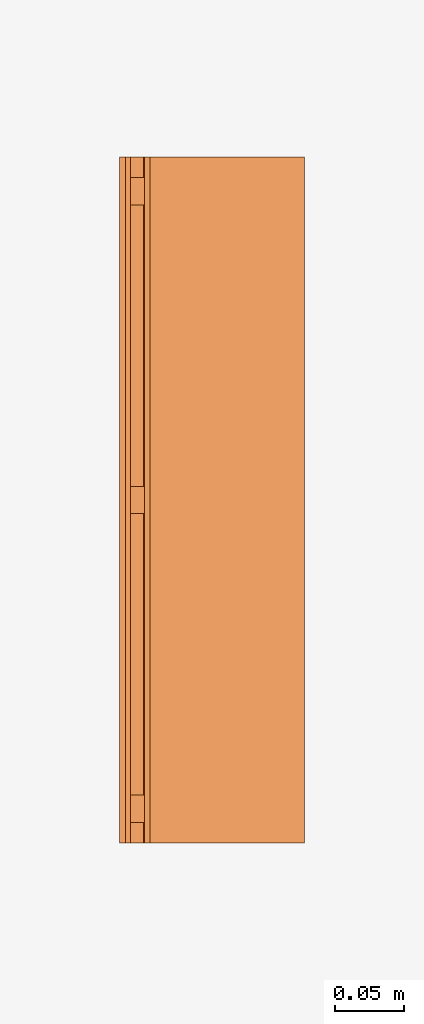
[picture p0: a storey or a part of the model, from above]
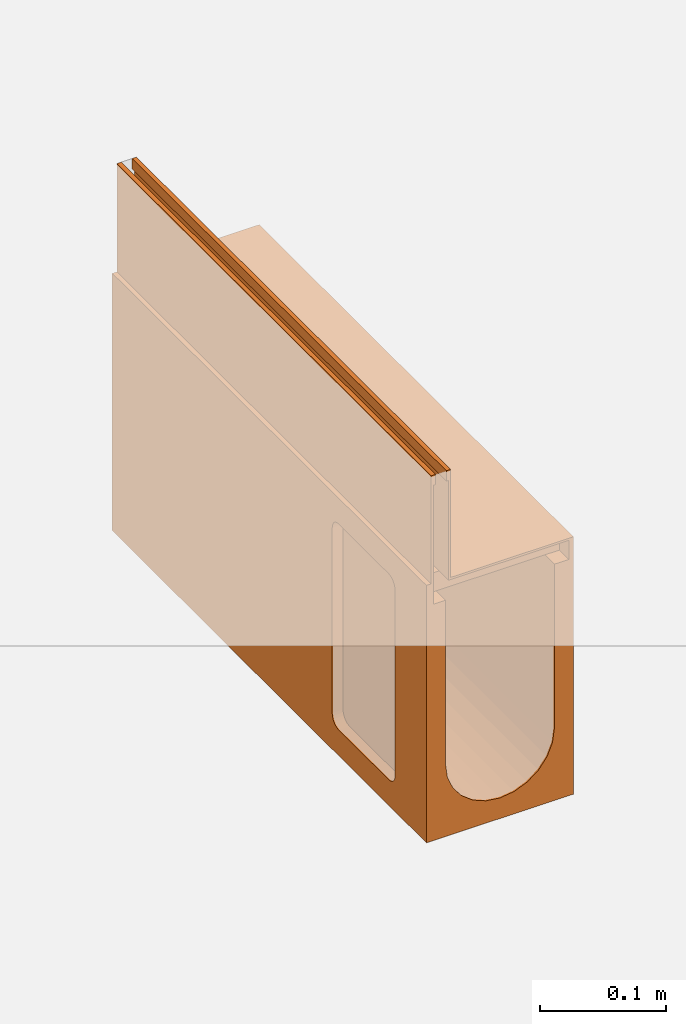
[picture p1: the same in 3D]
Properties of the parts of a building model (IFC2X3)

# File
Description: ViewDefinition [CoordinationView]
File name: 24201.ifc
Time: 2013-10-30T12:03:49
Written by: Autodesk Revit 2013
Made in: 20120221_2030(x64)

# IfcProject, Project Number
LongName: Project Name; Phase: Project Status

# IfcSite, Default
RefLatitude: 42, 21, 30, 344238; RefLongitude: -71, -3, -35, -194702; RefElevation: 0 mm

# IfcBuilding
Pset_BuildingCommon - NumberOfStoreys: 1
Other - Project Number: Project Number; Project Status: Project Status; Client Name: Owner; Project Issue Date: Issue Date; Project Address: ## Street City, State Zip; Project Name: Project Name

# IfcBuildingStorey, Level 1
LongName: Level 1; Elevation: 0 mm
Constraints - Elevation Base: 0; Elevation: 0 mm
Graphics - Color: 0; Symbol: M_Level Head - Circle: M_Level Head - Circle; Line Weight: 1; Symbol at End 2 Default: yes; Line Pattern: Center; Symbol at End 1 Default: no
Identity Data - Structural: no; Building Story: yes; Name: Level 1
Dimensions - Computation Height: 0 mm

# IfcBuildingElementProxy: 24201 - No 20.1J Constant Depth Channel - 500mm LG - Invert Depth 230mm, Civil-Drainage-Channel-ACO-MultiDrain-M100DS-Brickslot-Channel-System:24201 - No 20.1J Constant Depth Channel - 500mm LG - Invert Depth 230mm:24201 - No 20.1J Constant Depth Channel - 500mm LG - Invert Depth 230mm:196059
In: Level 1
Material: Stainless Steel (F), Vienite® Synthetic Resin Concrete
Dimensions - Volume: 5654234 mm3; FloorCut_Length: -500 mm; EndCap Position: 500 mm; Custom_Void_length: 0 mm; Brickslot Void Length: 500 mm; Brickslot Void Depth: 0 mm; Brickslot Access Unit Void Depth: -6500 mm; Brickslot Access Unit Void Bottom Depth: -6605 mm; Length: 1000 mm; FloorCut_Depth: 250 mm; InvDepth: 180 mm; FloorCut_Width: 135 mm; GratingLength: -1000 mm; Brickslot Access Unit Floor Cut Length: 500 mm; Floor Cut Gap: 105 mm; ShallowInvDepth: 55 mm; EndCap_Height: 250 mm; Length Drain: -500 mm; ShallowOverallDepth: 75 mm; Depth: 250 mm
Construction - 23404_Universal Endcap (Male End): no; 23404_Universal Endcap (Female End): no; 23477_Load Class C250 & D400_Brickslot_Access Unit_Stainless Steel_500mm Long: no; 23475_Load Class C250 & D400_Brickslot Grating_Stainless Steel_1000mm Long: no; 23476_Load Class C250 & D400_Brickslot Grating_Stainless Steel_500mm Long: yes; Constant Depth Junction Channel: yes; Shallow Depth Channel: no; Constant Depth Channel: no; 23410_Sump Unit: no; Shallow Depth Channel with seal: no
Constraints - Moves With Nearby Elements: no; Level: Level: Level 1
Phasing - Phase Created: New Construction
Pset_BuildingElementProxyCommon - Reference: 24201 - No 20.1J Constant Depth Channel - 500mm LG - Invert Depth 230mm
Identity Data - Maintenance guidelines: http://www.aco.co.uk/download.php?id=173; Cost: 0; URL: www.aco.co.uk; Watermark 2: This file is water marked and users are prohibited to reproduce, adapt, distribute this information; Type Comments: ACO MultiDrain M100DS 20.1J Constant Depth Junction Channel 500mm Long; Watermarked With: BIM Manager Premium Suite; Telephone: +44 (0)1462 816666; Watermark 1: This file is the property of ACO Technologies PLC; Address: ACO Business Park, Hitchin Road, Shefford, Bedfordshire, United Kingdom SG17 5TE; e-mail Sales: customersupport@aco.co.uk; OmniClass Title: Rainwater Removal; Model Description: Channel drainage system; e-mail Technical: technical@aco.co.uk; Product Page URL: http://www.aco.co.uk/product_detail.php?id=58; Assembly Code: D2040; Manufacturer: ACO Technologies plc - ACO Water Management Division; Price: POA - contact ACO; Installation guidelines: http://www.aco.co.uk/download.php?id=173; Model: ACO MultiDrain MDS Brickslot- M100DS; Product Code: 24201; Product brochure: http://www.aco.co.uk/download.php?id=173; OmniClass Number: 23.70.50.24; Fax: +44 (0)1462 815895; Watermarked By: www.aco.co.uk; Assembly Description: Rain Water Drainage
Green Building Properties - Channel Recycled Material Content: 20% minimum; Channel Recyclable: Fully recyclable; Edge Rail Recyclable: Fully recyclable; Edge Rail Recycled Material Content: Between 40% - 90%
Data - Load Class: A 15 - D 400; Pre-formed Outlet Ø: N/A; Concrete Surround Volume - Load Class D 400 - Concrete Pavement: 0.21m³/m; Invert Depth: 230mm; Concrete Surround Volume - Load Class A 15 - Concrete Pavement: 0.09m³/m; Product Standard: BS EN 1433:2002, CE marked; Channel C.S.A: 0.017m²; Product Dimensions: 500mm x 135mm x 250mm (LxWxH); Product Weight: 11.8 Kg; Concrete Surround Volume - Load Class B 125 - C 250 - Concrete Pavement: 0.14m³/m; Installation - Concrete Grade: Refer to brochure; Hydraulic Performance: http://www.aco.co.uk/download.php?id=173; ACO Hydraulic Design Software: http://www.acodesign.co.uk
Model Properties - Brickslot Grating Product code 23475: N/A; Brickslot Access Unit Product code 23477: Load Class C250/D400 - Brickslot Access Unit Stainless Steel - 500mm long x 105mm high -10mm Slot- Intake area - 1000mm²/m - 6.4 Kg; Brickslot Grating Product code 23476: Load Class C250/D400 - Brickslot Stainless Steel - 500mm long x 105mm high - Intake area -10mm Slot- 1000mm²/m - 3.3 Kg; End Cap Product code 23404: No 306 Universl End Cap - 135mm wide x 300mm long - Spigot Ø110mm x 50mm long - Silver - Polypropylene - 0.16kg
Other - Revision: 1; Created By: www.aco.co.uk
General - TagNumber: 0; SerialNumber: 0
Materials and Finishes - Edge Rail Colour: Self; Channel Colour: Brown; Channel Material: Vienite® Synthetic Resin Concrete; Edge Rail Material: Stainless Steel Grade 304

# IfcOpeningElement: Recess (2)
In: Level 1
Dimensions - Volume: 9982180000 mm3; Thickness: 400 mm; Perimeter: 20000 mm; Area: 25000000 mm2
Phasing - Phase Created: New Construction
Constraints - Room Bounding: yes; Height Offset From Level: 0 mm; Related to Mass: no; Level: Level: Level 1
Structural - Structural: no; Enable Analytical Model: no
Analytical Properties - Thermal mass: 543920; Heat Transfer Coefficient (U): 2.0925; Roughness: 1; Thermal Resistance (R): 0.477897; Absorptance: 0.1
Graphics - Coarse Scale Fill Color: 0
Construction - Default Thickness: 400 mm; Function: 0
Materials and Finishes - Structural Material: Earth

# IfcSlab: Floor:Generic Floor - 400mm, Floor:Generic Floor - 400mm:193825
In: Level 1
PredefinedType: FLOOR; Material: Earth 400 mm
Dimensions - Volume: 9982180000 mm3; Thickness: 400 mm; Perimeter: 20000 mm; Area: 25000000 mm2
Phasing - Phase Created: New Construction
Constraints - Room Bounding: yes; Height Offset From Level: 0 mm; Related to Mass: no; Level: Level: Level 1
Structural - Structural: no; Enable Analytical Model: no
Pset_SlabCommon - Reference: Generic Floor - 400mm; IsExternal: no; LoadBearing: yes
Analytical Properties - Thermal mass: 543920; Heat Transfer Coefficient (U): 2.0925; Roughness: 1; Thermal Resistance (R): 0.477897; Absorptance: 0.1
Graphics - Coarse Scale Fill Color: 0
Construction - Default Thickness: 400 mm; Function: 0
Materials and Finishes - Structural Material: Earth
